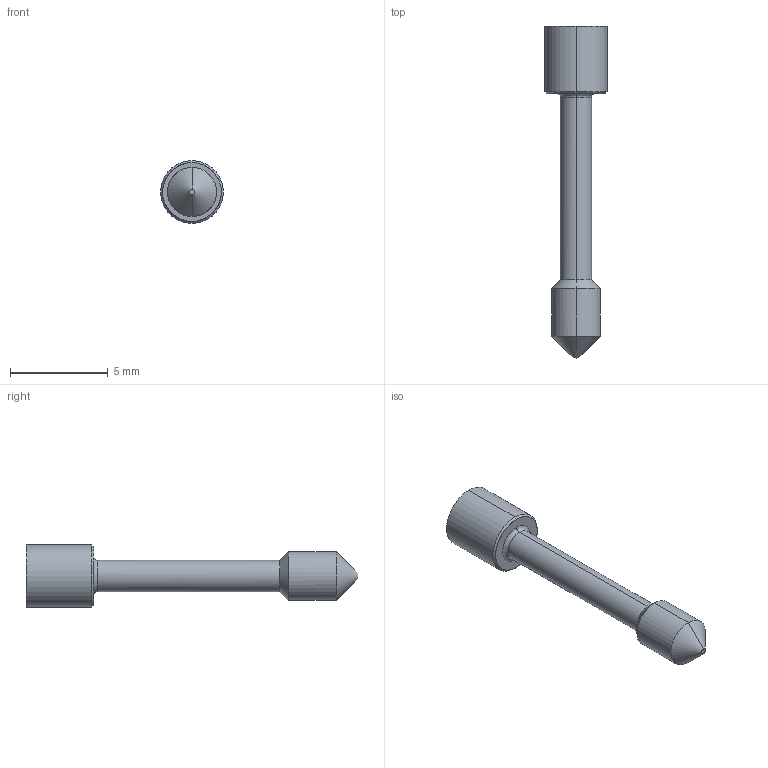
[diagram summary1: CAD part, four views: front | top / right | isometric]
IGES file: header records copied from the file, then geometry measured from it (millimetres).
Start section: START RECORD GO HERE.
Global section: file name: ia321720.igs; native system: DASSAULT SYSTEMES CATIA V5 R20 - www.3ds.com; preprocessor: CATIA Version 5 Release 20 ; author: Utente; organization: NB04-ASUS; date: 20201108.074339; units: millimetre
Bounding box: 3.2 x 16.95 x 3.2 mm (x, y, z)
Surface area: 129.4 mm2 (no closed solid volume)
Topology: 0 solids, 0 shells, 54 faces, 262 edges, 262 vertices
Faces by surface type: revolution 32, plane 22
